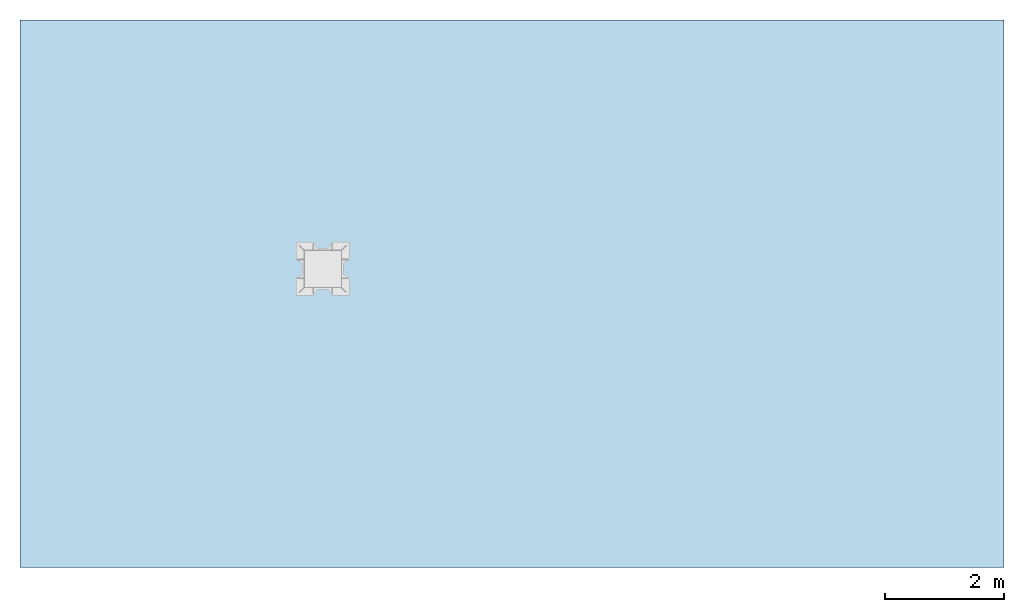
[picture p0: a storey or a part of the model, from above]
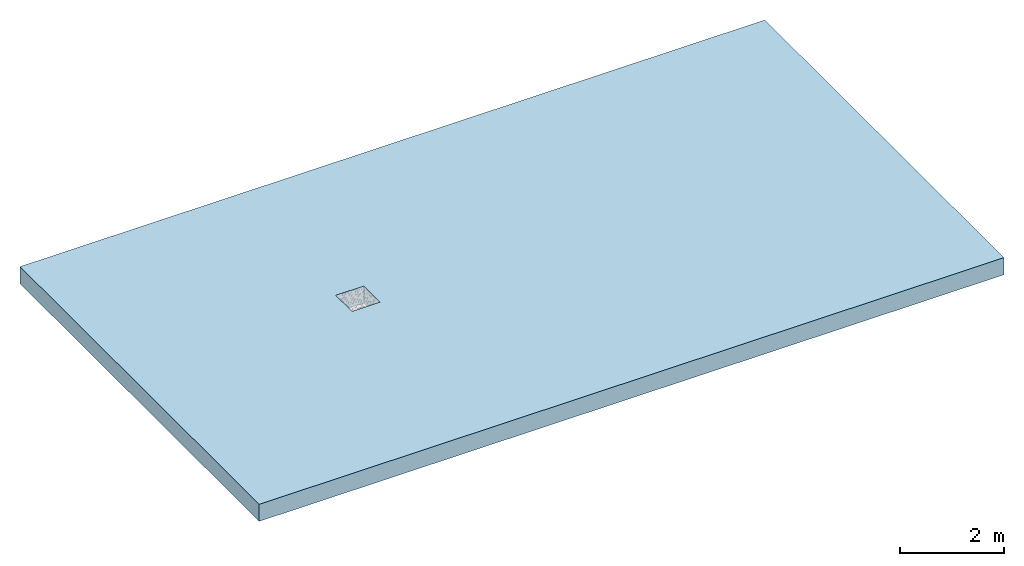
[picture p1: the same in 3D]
Properties of the parts of a building model (IFC2X3)

# File
Description: ViewDefinition [CoordinationView]
File name: 44316.ifc
Time: 2013-09-04T16:18:03
Written by: Autodesk Revit 2013
Made in: 20120221_2030(x64)

# IfcProject, Project Number
LongName: Project Name; Phase: Project Status

# IfcSite, Default
RefLatitude: 42, 21, 30, 344238; RefLongitude: -71, -3, -35, -194702; RefElevation: 0 mm

# IfcBuilding
Pset_BuildingCommon - NumberOfStoreys: 1
Other - Project Address: ## Street City, State Zip; Project Number: Project Number; Client Name: Owner; Project Name: Project Name; Project Issue Date: Issue Date; Project Status: Project Status

# IfcBuildingStorey, Level 1
LongName: Level 1; Elevation: 0 mm
Constraints - Elevation Base: 0; Elevation: 0 mm
Graphics - Symbol at End 2 Default: yes; Line Weight: 1; Symbol: M_Level Head - Circle: M_Level Head - Circle; Line Pattern: Center; Color: 0; Symbol at End 1 Default: no
Dimensions - Computation Height: 0 mm
Identity Data - Name: Level 1; Building Story: yes; Structural: no

# IfcFlowTerminal: 44316, Access Chambers - 550,700,900:44316:44316:346357
In: Level 1
Constraints - Level: Level: Level 1; Moves With Nearby Elements: no
Phasing - Phase Created: New Construction
Identity Data - Mark: 61; Model Description: High capacity slot drainage channel system; Fax: +44 (0)1462 815895; Telephone: +44 (0)1462 816666; Type Comments: ACO Qmax 550 700 900 Access Chamber with F 900 Slotted Cover & Frame; Manufacturer: ACO Technologies plc - ACO Water Management Division; URL: www.aco.co.uk; Product brochure: http://www.aco.co.uk/download.php?id=220; Installation guidelines: http://www.aco.co.uk/download.php?id=220; Cost: 0; Product Code: 44316; OmniClass Number: 23.70.50.24; e-mail Technical: technical@aco.co.uk; Product Page URL: http://www.aco.co.uk/product_detail.php?id=79; Maintenance guidelines: http://www.aco.co.uk/download.php?id=220; OmniClass Title: Rainwater Removal; Assembly Code: D2040; Price: POA - contact ACO; Model: ACO Qmax 550 700 900 Access and Silt Chambers; e-mail Sales: customersupport@aco.co.uk; Address: ACO Business Park, Hitchin Road, Shefford, Bedfordshire, United Kingdom SG17 5TE; Assembly Description: Rain Water Drainage
General - TagNumber: 0.000000; SerialNumber: 0.000000
Materials and Finishes - Cover & Frame Colour: Black; Cover & Frame Finish: Water Based Paint Coating; Access Chamber Material: Medium Density Polyethylene; Cover & Frame Material: Ductile Iron; Access Chamber Colour: Black
Construction - V_Solid Cover: no; V_Slotted Cover: yes
Data - ACO Hydraulic Design Software: http://www.acodesign.co.uk; Drainage Slot Width: 21mm; Product Standard: BS EN 124:1994 CE marked; Product Weight: 181 kg; Load Class: A 15 - F 900; Product Dimensions: 870mm x 800mm x 1500mm (LxWxH); Drainage Slot Intake area: 120182mm²; Installation - Reinforcement Details: Refer to brochure; Installation - Concrete Grade: Refer to brochure
Dimensions - Floor Opening Width: 621 mm; Top of Access-IO-Silt: -150 mm; Width Overall: 870 mm; Coarse_Chamber_Depth: -1500 mm; Coarse_Cover_Depth: -150 mm; Depth Overall: 1500
Green Building Properties - Access Chamber Recyclable: Fully recyclable; Cover & Frame Recyclable: Fully recyclable; Access Chamber Recycled Material Content: Variable %; Cover & Frame Recycled Material Content: Between 40% - 90%
Other - CreatedBy: www.aco.co.uk; Revision: 1

# IfcOpeningElement: Opening
In: Level 1
Phasing - Phase Created: New Construction
Dimensions - Area: 151084359 mm2; Perimeter: 51360 mm; Thickness: 400 mm; Volume: 60433743600 mm3
Constraints - Room Bounding: yes; Related to Mass: no; Height Offset From Level: 0 mm; Level: Level: Level 1
Structural - Enable Analytical Model: no; Structural: no
Construction - Function: 0; Default Thickness: 400 mm
Analytical Properties - Absorptance: 0.1; Roughness: 1
Graphics - Coarse Scale Fill Color: 0
Materials and Finishes - Structural Material: Plant

# IfcSlab: Floor:Generic Floor - 400mm, Floor:Generic Floor - 400mm:193825
In: Level 1
PredefinedType: FLOOR; Material: Plant 400 mm
Phasing - Phase Created: New Construction
Dimensions - Area: 151084359 mm2; Perimeter: 51360 mm; Thickness: 400 mm; Volume: 60433743600 mm3
Constraints - Room Bounding: yes; Related to Mass: no; Height Offset From Level: 0 mm; Level: Level: Level 1
Structural - Enable Analytical Model: no; Structural: no
Pset_SlabCommon - Reference: Generic Floor - 400mm; IsExternal: no; LoadBearing: yes
Construction - Function: 0; Default Thickness: 400 mm
Analytical Properties - Absorptance: 0.1; Roughness: 1
Graphics - Coarse Scale Fill Color: 0
Materials and Finishes - Structural Material: Plant
